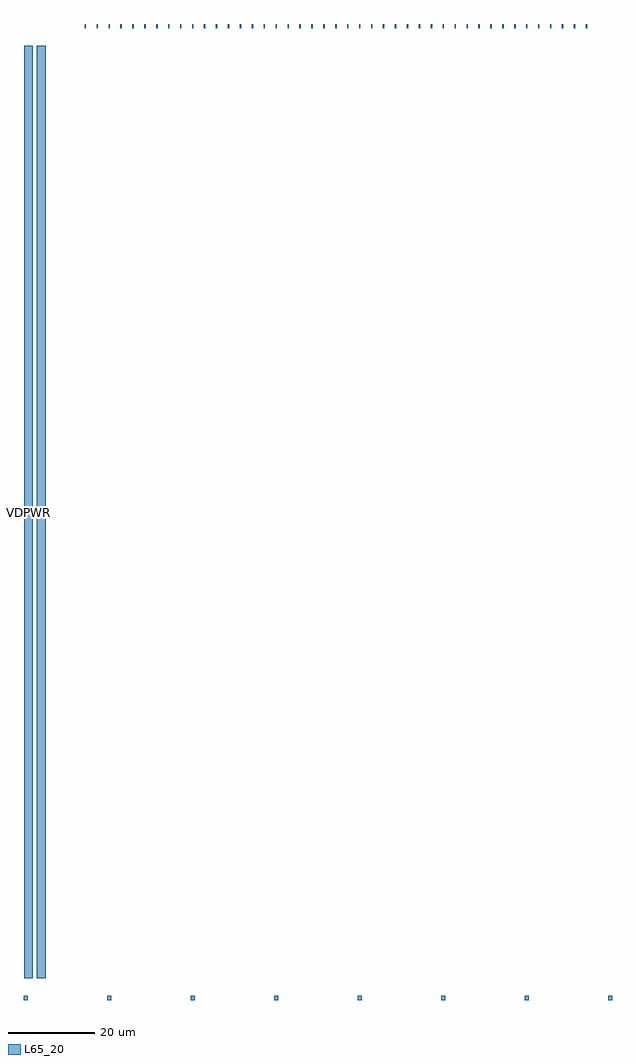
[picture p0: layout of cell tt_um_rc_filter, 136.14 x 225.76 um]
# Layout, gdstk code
import gdstk
lib = gdstk.Library(unit=1e-6, precision=1e-09)
def R(c, l, rs):  # rectangles x0, y0, x1, y1
    for r in rs: c.add(gdstk.rectangle(r[:2], r[2:], *l))
def A(c, l, x, y, w, h, nx, ny, dx, dy):  # array of equal rectangles
    R(c, l, [(x+i*dx, y+j*dy, x+i*dx+w, y+j*dy+h) for i in range(nx) for j in range(ny)])
L65_20 = (65, 20)

tt_um_rc_filter = lib.new_cell('tt_um_rc_filter')
A(tt_um_rc_filter, L65_20, 0.93, 0, 0.9, 1, 8, 1, 19.32, 0)
A(tt_um_rc_filter, L65_20, 15.03, 224.76, 0.3, 1, 43, 1, 2.76, 0)
R(tt_um_rc_filter, L65_20, [(1,5,3,220.76), (4,5,6,220.76)])
tt_um_rc_filter.add(gdstk.Label('VDPWR', (2,112.88), layer=66, texttype=0))
tt_um_rc_filter.add(gdstk.Label('VGND', (5,112.88), layer=66, texttype=0))

lib.write_gds('tt_um_rc_filter.gds')
